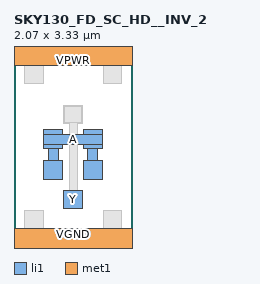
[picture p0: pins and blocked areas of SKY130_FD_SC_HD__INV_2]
MACRO SKY130_FD_SC_HD__INV_2
 CLASS CORE ;
 FOREIGN SKY130_FD_SC_HD__INV_2 0 0 ;
 SIZE 2.07 BY 3.33 ;
 ORIGIN 0 0 ;
 SYMMETRY X Y R90 ;
 SITE unit ;
  PIN VPWR
   DIRECTION INOUT ;
   USE POWER ;
   SHAPE ABUTMENT ;
    PORT
     CLASS CORE ;
       LAYER li1 ;
        RECT 0.00000000 3.09000000 2.07000000 3.57000000 ;
       LAYER met1 ;
        RECT 0.00000000 3.09000000 2.07000000 3.57000000 ;
    END
  END VPWR

  PIN VGND
   DIRECTION INOUT ;
   USE POWER ;
   SHAPE ABUTMENT ;
    PORT
     CLASS CORE ;
       LAYER li1 ;
        RECT 0.00000000 -0.24000000 2.07000000 0.24000000 ;
       LAYER met1 ;
        RECT 0.00000000 -0.24000000 2.07000000 0.24000000 ;
    END
  END VGND

  PIN Y
   DIRECTION INOUT ;
   USE SIGNAL ;
   SHAPE ABUTMENT ;
    PORT
     CLASS CORE ;
       LAYER li1 ;
        RECT 0.87000000 0.58000000 1.20000000 0.91000000 ;
    END
  END Y

  PIN A
   DIRECTION INOUT ;
   USE SIGNAL ;
   SHAPE ABUTMENT ;
    PORT
     CLASS CORE ;
       LAYER li1 ;
        RECT 0.52500000 1.09500000 0.85500000 1.42500000 ;
        RECT 1.21500000 1.09500000 1.54500000 1.42500000 ;
        RECT 0.60500000 1.42500000 0.77500000 1.63500000 ;
        RECT 1.29500000 1.42500000 1.46500000 1.63500000 ;
        RECT 0.52500000 1.63500000 0.85500000 1.71500000 ;
        RECT 1.21500000 1.63500000 1.54500000 1.71500000 ;
        RECT 0.52500000 1.71500000 1.54500000 1.88500000 ;
        RECT 0.52500000 1.88500000 0.85500000 1.96500000 ;
        RECT 1.21500000 1.88500000 1.54500000 1.96500000 ;
    END
  END A

 OBS
    LAYER polycont ;
     RECT 0.60500000 1.17500000 0.77500000 1.34500000 ;
     RECT 1.29500000 1.17500000 1.46500000 1.34500000 ;
     RECT 0.60500000 1.71500000 0.77500000 1.88500000 ;
     RECT 1.29500000 1.71500000 1.46500000 1.88500000 ;

    LAYER pdiffc ;
     RECT 0.95000000 2.15000000 1.12000000 2.32000000 ;
     RECT 0.26000000 2.86000000 0.43000000 3.03000000 ;
     RECT 1.64000000 2.86000000 1.81000000 3.03000000 ;

    LAYER ndiffc ;
     RECT 0.26000000 0.30000000 0.43000000 0.47000000 ;
     RECT 1.64000000 0.30000000 1.81000000 0.47000000 ;
     RECT 0.95000000 0.66000000 1.12000000 0.83000000 ;

    LAYER li1 ;
     RECT 0.00000000 -0.24000000 2.07000000 0.24000000 ;
     RECT 0.18000000 0.24000000 0.51000000 0.55000000 ;
     RECT 1.56000000 0.24000000 1.89000000 0.55000000 ;
     RECT 0.87000000 0.58000000 1.20000000 0.91000000 ;
     RECT 0.52500000 1.09500000 0.85500000 1.42500000 ;
     RECT 1.21500000 1.09500000 1.54500000 1.42500000 ;
     RECT 0.60500000 1.42500000 0.77500000 1.63500000 ;
     RECT 1.29500000 1.42500000 1.46500000 1.63500000 ;
     RECT 0.52500000 1.63500000 0.85500000 1.71500000 ;
     RECT 1.21500000 1.63500000 1.54500000 1.71500000 ;
     RECT 0.52500000 1.71500000 1.54500000 1.88500000 ;
     RECT 0.52500000 1.88500000 0.85500000 1.96500000 ;
     RECT 1.21500000 1.88500000 1.54500000 1.96500000 ;
     RECT 0.87000000 2.07000000 1.20000000 2.40000000 ;
     RECT 0.18000000 2.78000000 0.51000000 3.09000000 ;
     RECT 1.56000000 2.78000000 1.89000000 3.09000000 ;
     RECT 0.00000000 3.09000000 2.07000000 3.57000000 ;

    LAYER viali ;
     RECT 1.64000000 -0.08500000 1.81000000 0.08500000 ;
     RECT 0.95000000 0.66000000 1.12000000 0.83000000 ;
     RECT 0.95000000 2.15000000 1.12000000 2.32000000 ;
     RECT 0.26000000 3.24500000 0.43000000 3.41500000 ;

    LAYER met1 ;
     RECT 0.00000000 -0.24000000 2.07000000 0.24000000 ;
     RECT 0.89000000 0.60000000 1.18000000 0.89000000 ;
     RECT 0.96500000 0.89000000 1.10500000 2.09000000 ;
     RECT 0.89000000 2.09000000 1.18000000 2.38000000 ;
     RECT 0.00000000 3.09000000 2.07000000 3.57000000 ;

    LAYER via ;


    LAYER met2 ;


    LAYER via2 ;


    LAYER met3 ;


 END
END SKY130_FD_SC_HD__INV_2
